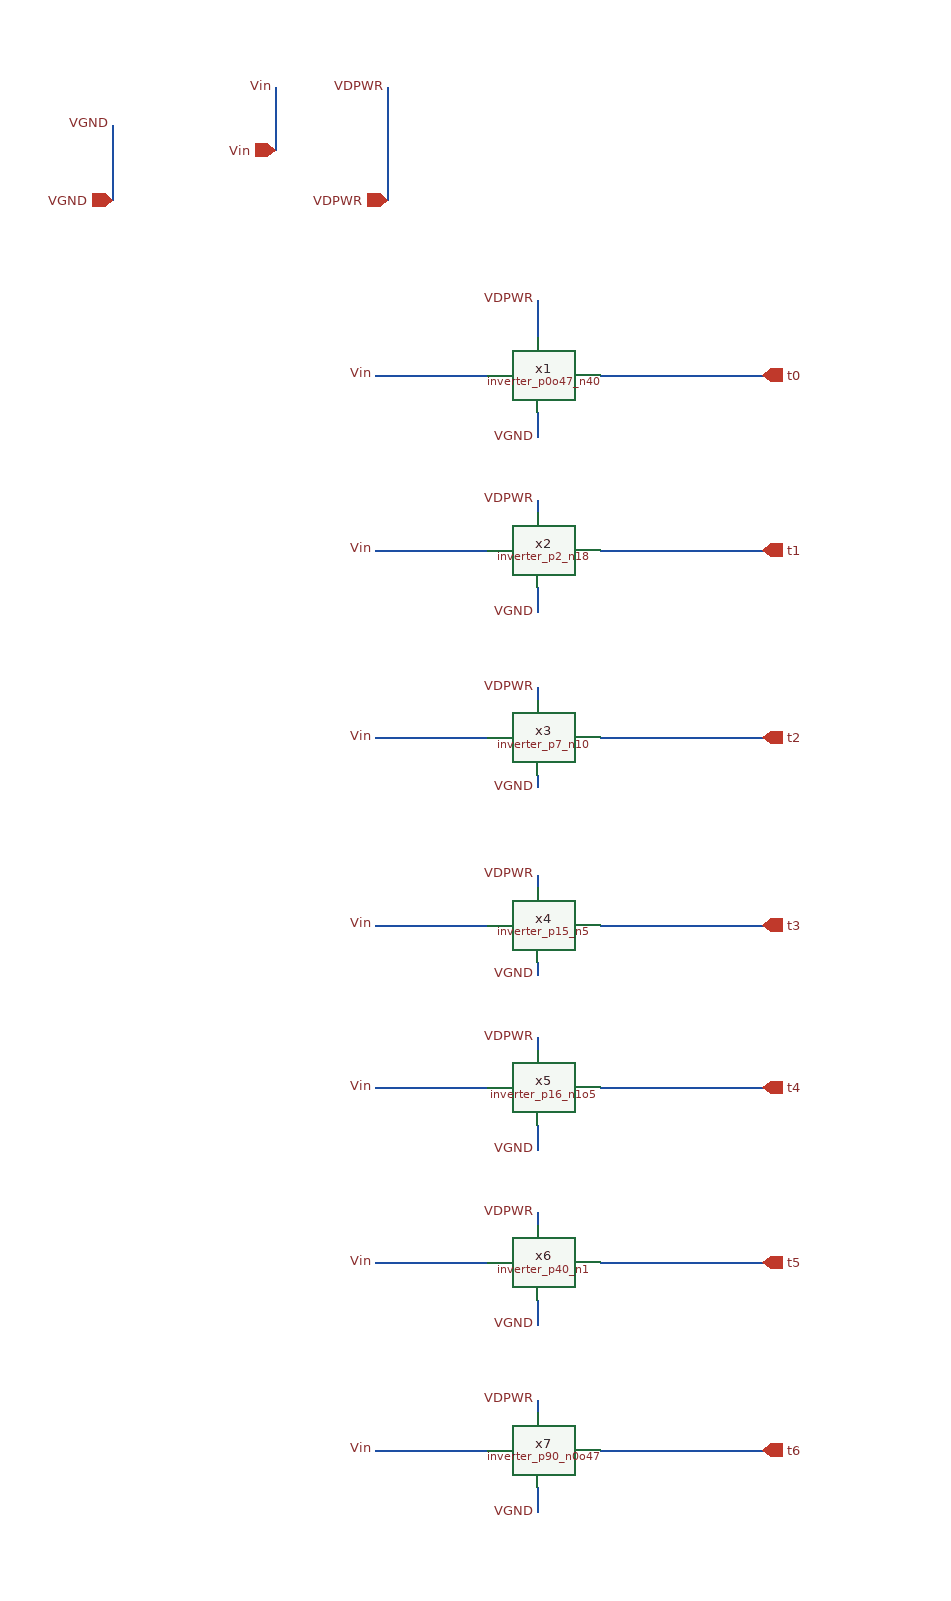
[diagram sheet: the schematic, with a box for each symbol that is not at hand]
v {xschem version=3.4.7 file_version=1.2}
G {}
K {}
V {}
S {}
E {}
N -150 -260 -150 -230 {lab=VDPWR}
N -240 -260 -240 -230 {lab=Vin}
N -370 -230 -370 -190 {lab=VGND}
N -30 -90 -30 -60 {lab=VDD}
N -30 70 -30 80 {lab=VDPWR}
N -30 0 -30 20 {lab=VGND}
N -30 140 -30 160 {lab=VGND}
N -30 220 -30 230 {lab=VDPWR}
N -30 290 -30 300 {lab=VGND}
N -30 370 -30 380 {lab=VDPWR}
N -30 440 -30 450 {lab=VGND}
N -30 500 -30 510 {lab=VDPWR}
N -30 570 -30 590 {lab=VGND}
N -30 640 -30 650 {lab=VDPWR}
N -30 710 -30 730 {lab=VGND}
N -30 790 -30 800 {lab=VDPWR}
N -30 860 -30 880 {lab=VGND}
N -160 -30 -70 -30 {lab=Vin}
N -160 830 -70 830 {lab=Vin}
N -160 680 -70 680 {lab=Vin}
N -160 540 -70 540 {lab=Vin}
N -160 410 -70 410 {lab=Vin}
N -160 260 -70 260 {lab=Vin}
N -160 110 -70 110 {lab=Vin}
N 20 -30 150 -30 {lab=t0}
N 20 110 150 110 {lab=t1}
N 20 260 150 260 {lab=t2}
N 20 410 150 410 {lab=t3}
N 20 540 150 540 {lab=t4}
N 20 680 150 680 {lab=t5}
N 20 830 150 830 {lab=t6}
N -240 -230 -240 -210 {lab=Vin}
N -370 -190 -370 -170 {lab=VGND}
N -150 -230 -150 -170 {lab=VDPWR}
C {lab_wire.sym} -370 -230 0 0 {name=p1 sig_type=std_logic lab=VGND}
C {lab_wire.sym} -240 -260 0 0 {name=p4 sig_type=std_logic lab=Vin}
C {lab_wire.sym} -150 -260 0 0 {name=p5 sig_type=std_logic lab=VDPWR}
C {lab_wire.sym} -30 -90 0 0 {name=p6 sig_type=std_logic lab=VDPWR}
C {lab_wire.sym} -30 70 0 0 {name=p7 sig_type=std_logic lab=VDPWR}
C {lab_wire.sym} -30 20 0 0 {name=p8 sig_type=std_logic lab=VGND}
C {lab_wire.sym} -30 160 0 0 {name=p9 sig_type=std_logic lab=VGND}
C {lab_wire.sym} -30 220 0 0 {name=p10 sig_type=std_logic lab=VDPWR}
C {lab_wire.sym} -30 300 0 0 {name=p11 sig_type=std_logic lab=VGND}
C {lab_wire.sym} -30 370 0 0 {name=p12 sig_type=std_logic lab=VDPWR}
C {lab_wire.sym} -30 450 0 0 {name=p13 sig_type=std_logic lab=VGND}
C {lab_wire.sym} -30 500 0 0 {name=p14 sig_type=std_logic lab=VDPWR}
C {lab_wire.sym} -30 590 0 0 {name=p15 sig_type=std_logic lab=VGND}
C {lab_wire.sym} -30 640 0 0 {name=p16 sig_type=std_logic lab=VDPWR}
C {lab_wire.sym} -30 730 0 0 {name=p17 sig_type=std_logic lab=VGND}
C {lab_wire.sym} -30 790 0 0 {name=p18 sig_type=std_logic lab=VDPWR}
C {lab_wire.sym} -30 880 0 0 {name=p19 sig_type=std_logic lab=VGND}
C {lab_wire.sym} -160 -30 0 0 {name=p20 sig_type=std_logic lab=Vin}
C {lab_wire.sym} -160 110 0 0 {name=p30 sig_type=std_logic lab=Vin}
C {lab_wire.sym} -160 260 0 0 {name=p31 sig_type=std_logic lab=Vin}
C {lab_wire.sym} -160 410 0 0 {name=p32 sig_type=std_logic lab=Vin}
C {lab_wire.sym} -160 540 0 0 {name=p33 sig_type=std_logic lab=Vin}
C {lab_wire.sym} -160 680 0 0 {name=p34 sig_type=std_logic lab=Vin}
C {lab_wire.sym} -160 830 0 0 {name=p35 sig_type=std_logic lab=Vin}
C {/foss/designs/analog-circuit-design/sky25a-TIQ_ADC/xschem/INVERTER_SIZES/inverter_p15_n5.sym} -30 410 0 0 {name=x4}
C {/foss/designs/analog-circuit-design/sky25a-TIQ_ADC/xschem/INVERTER_SIZES/inverter_p16_n1o5.sym} -30 540 0 0 {name=x5}
C {/foss/designs/analog-circuit-design/sky25a-TIQ_ADC/xschem/INVERTER_SIZES/inverter_p40_n1.sym} -30 680 0 0 {name=x6}
C {/foss/designs/analog-circuit-design/sky25a-TIQ_ADC/xschem/INVERTER_SIZES/inverter_p2_n18.sym} -40 110 0 0 {name=x2}
C {/foss/designs/analog-circuit-design/sky25a-TIQ_ADC/xschem/INVERTER_SIZES/inverter_p7_n10.sym} -30 260 0 0 {name=x3}
C {/foss/designs/analog-circuit-design/sky25a-TIQ_ADC/xschem/INVERTER_SIZES/inverter_p90_n0o47.sym} -30 830 0 0 {name=x7}
C {/foss/designs/analog-circuit-design/sky25a-TIQ_ADC/xschem/INVERTER_SIZES/inverter_p0o47_n40.sym} -30 -30 0 0 {name=x1}
C {opin.sym} 150 -30 0 0 {name=p2 lab=t0}
C {opin.sym} 150 110 0 0 {name=p3 lab=t1}
C {opin.sym} 150 260 0 0 {name=p21 lab=t2}
C {opin.sym} 150 410 0 0 {name=p22 lab=t3}
C {opin.sym} 150 540 0 0 {name=p23 lab=t4}
C {opin.sym} 150 680 0 0 {name=p24 lab=t5}
C {opin.sym} 150 830 0 0 {name=p25 lab=t6}
C {ipin.sym} -240 -210 0 0 {name=p26 lab=Vin}
C {iopin.sym} -370 -170 0 0 {name=p27 lab=VGND}
C {iopin.sym} -150 -170 0 0 {name=p28 lab=VDPWR}
